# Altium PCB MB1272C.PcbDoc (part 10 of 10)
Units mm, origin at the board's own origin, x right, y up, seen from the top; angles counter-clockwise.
Board outline 101 x 71 mm, 6 copper layers (Top Layer, Signal Layer 1, Signal Layer 2, Signal Layer 3, Signal Layer 4, Bottom Layer), stack 1.552 mm thick; 520 components, 478 nets, 2156 pads, 1894 vias.

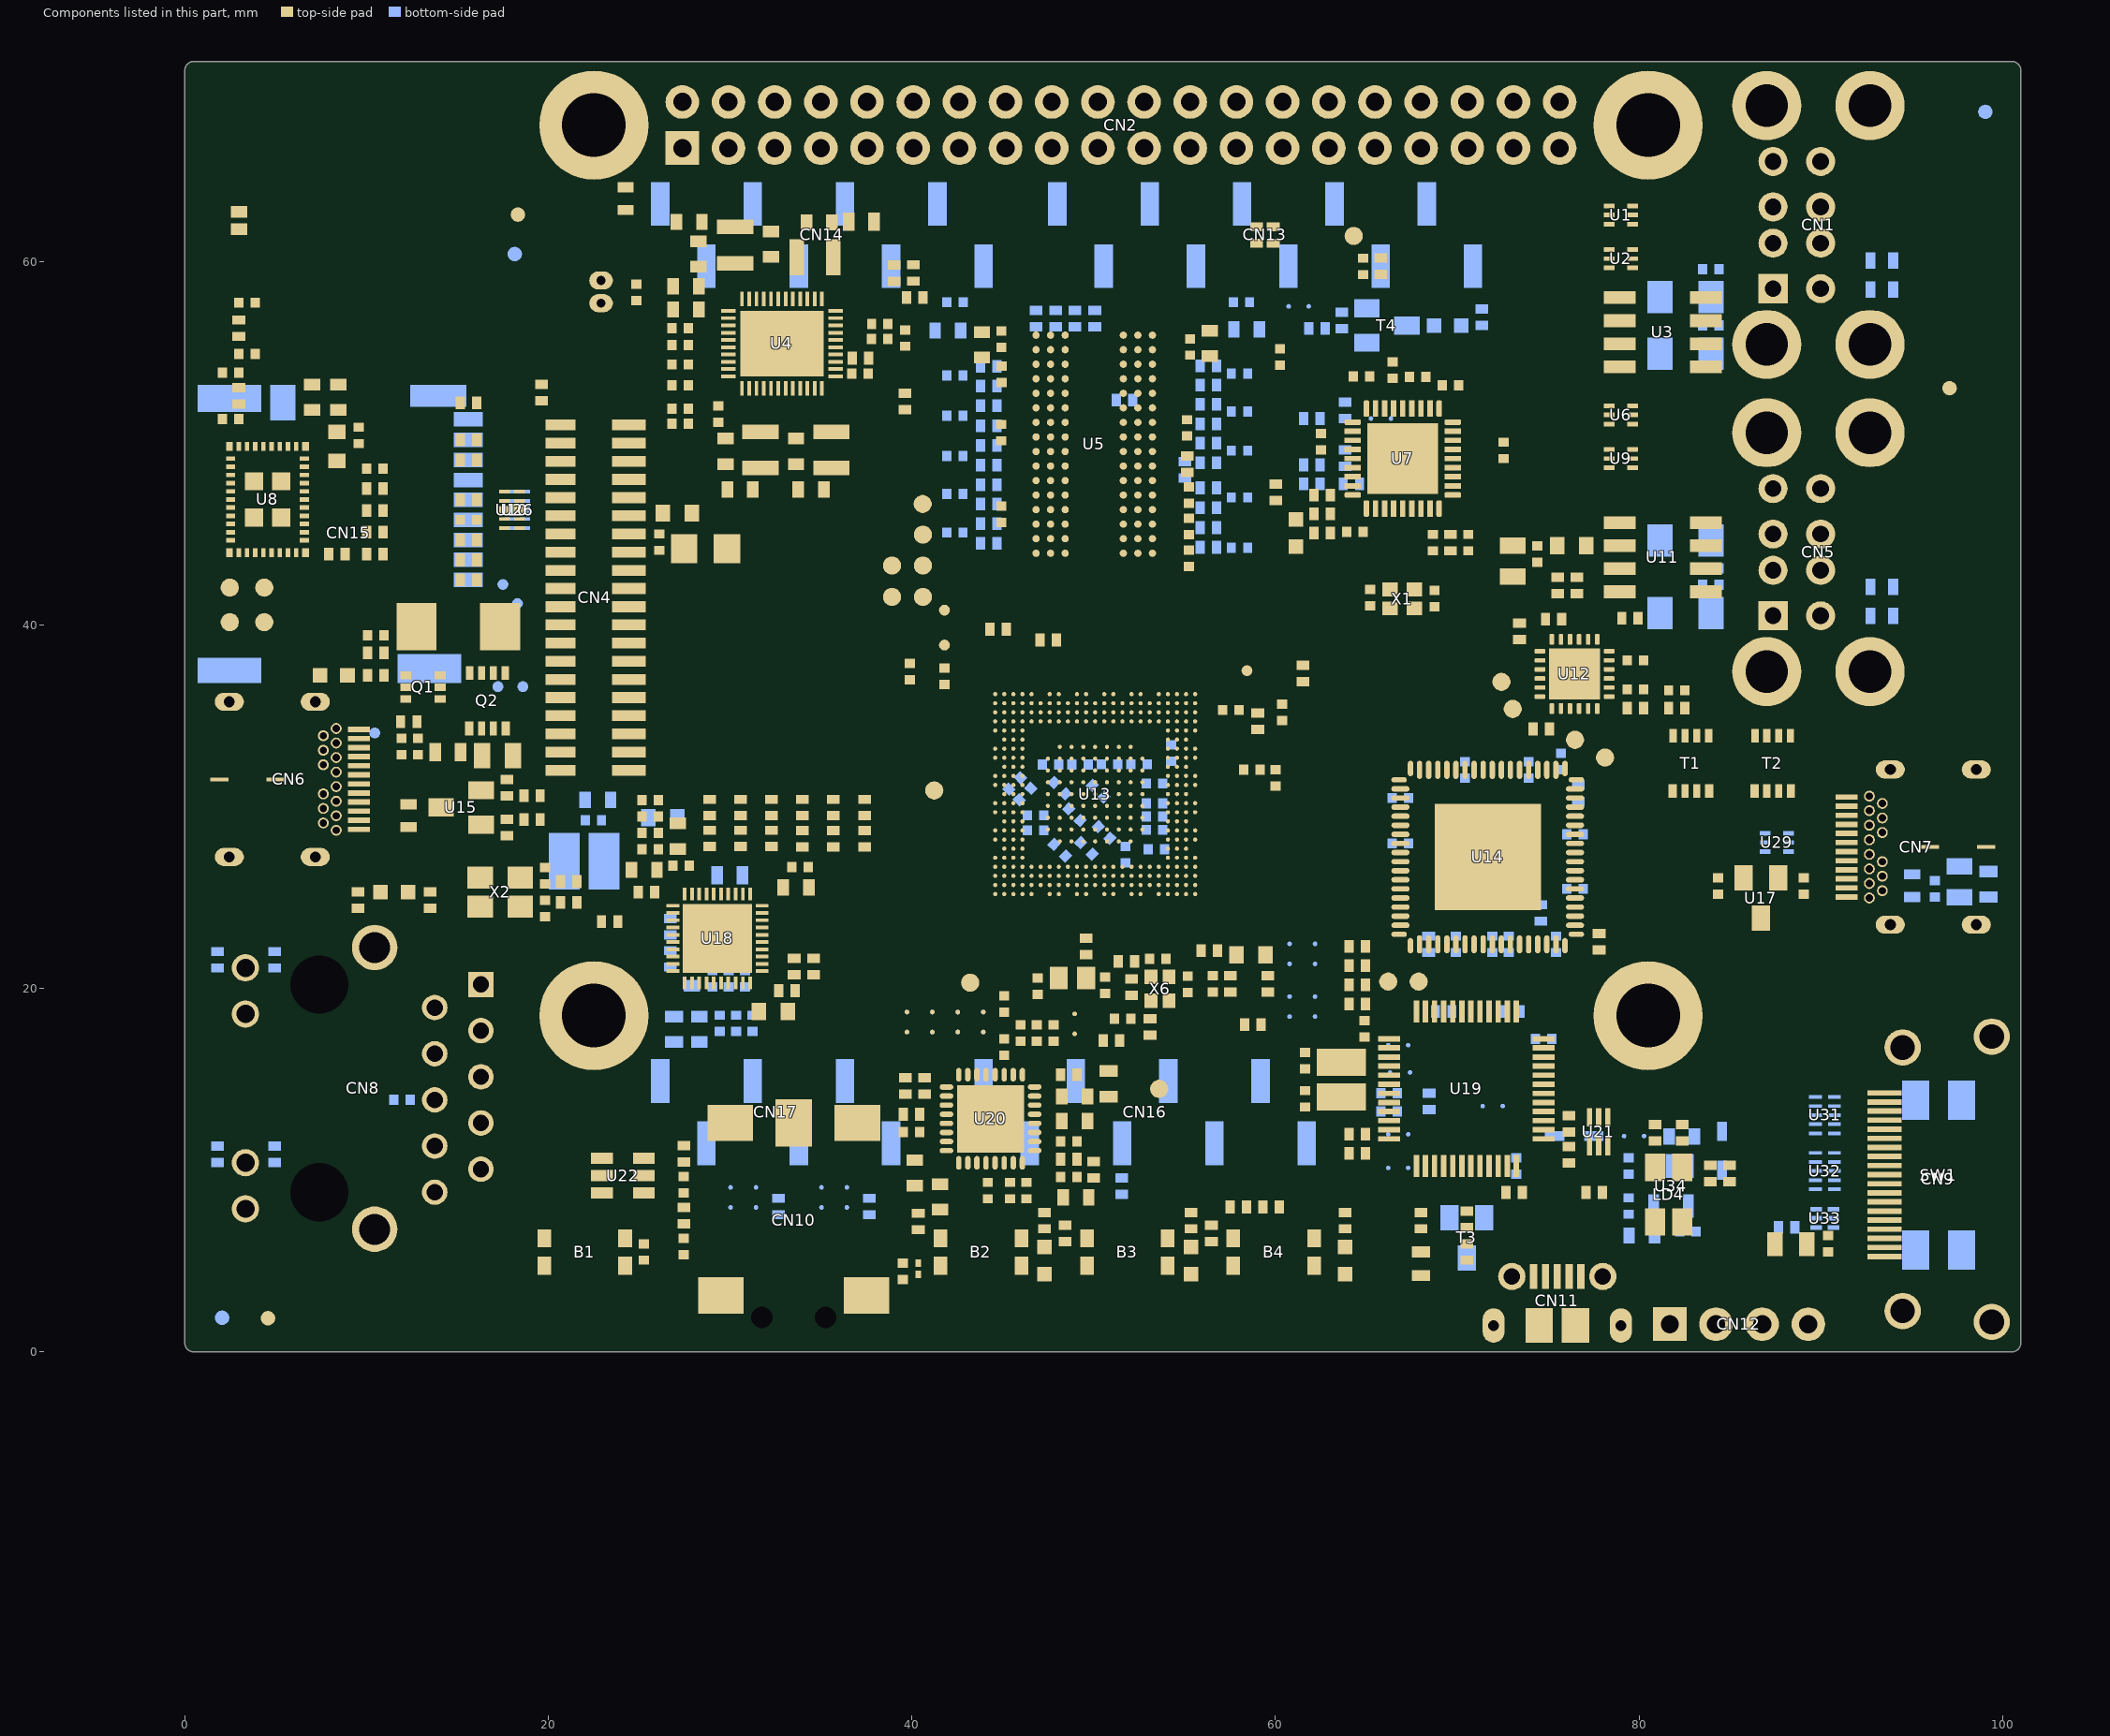
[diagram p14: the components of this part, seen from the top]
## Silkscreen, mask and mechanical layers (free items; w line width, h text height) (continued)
Drill Drawing:
  drawing of 549 lines, arcs and shapes, not listed
  text "PCB SPECIFICATIONS :" at 6.92,173.965 h3
  text "PCB : TYPE 4" at 155.276,173.613 h3
  text "MINIMUN PARAMETERS" at 192.17,173.59 h3
  text "A.   MATERIAL :" at 6.92,169.965 h3
  text "FR-4" at 45.42,169.965 h3
  text "TG-170" at 61.92,169.965 h3
  text "X  TG-150" at 80.17,169.965 h3
  text "TG-140" at 96.17,169.965 h3
  text "ASPECT-RATIO, AXE Z :" at 155.276,168.113 h3
  text "DEFAULT" at 192.17,168.09 h3
  text "B.   MATERIAL FAMILY :" at 6.92,166.965 h3
  text "N/A" at 45.42,166.965 h3
  text "C.   SOLDERMASK COLOR :" at 6.92,163.965 h3
  text "X  BLUE" at 45.42,163.965 h3
  text "WHITE" at 61.92,163.965 h3
  text "RED" at 80.17,163.965 h3
  text "BLACK" at 96.17,163.965 h3
  text "TRACKS : 0.090mm           / GAPS : 0.090mm" at 192.17,162.34 h3
  text "6:1 to 8:1 / LEVEL \"B\"" at 155.295,161.365 h3
  text "D.   SILKSCREEN COLOR :" at 6.92,160.965 h3
  text "X  WHITE" at 45.42,160.965 h3
  text "YELLOW" at 61.92,160.965 h3
  text "BLACK" at 80.17,160.965 h3
  text "Blue ink PANTONE 2955" at 96.17,160.965 h3
  text "MCU" at 192.495,158.265 h3
  text "E.   SURFACE FINISH :" at 6.92,157.965 h3
  text "X  ENIG" at 45.42,157.965 h3
  text "IMMERSION SILVER" at 61.92,157.965 h3
  text "IMMERSION TIN" at 96.17,157.965 h3
  text "HASL" at 45.42,154.965 h3
  text "HASL (PB-FREE)" at 61.92,154.965 h3
  text "GOLDEN FINGER" at 96.17,154.965 h3
  text "TRACKS : 0.090mm           / GAPS : 0.080mm" at 192.495,152.515 h3
  text "F.   IMPEDANCE CONTROL :" at 6.92,151.965 h3
  text "NO" at 45.42,151.965 h3
  text "X  YES  (SEE IMPEDANCE TABLE FOR DETAIL INFORMATION)" at 61.92,151.965 h3
  text "G.   THROUGH VIA :" at 6.92,148.965 h3
  text "PLUG THE VIAS WHICH ARE COVERED WITH SOLDERMASK ONE OR TWO SIDE." at 45.42,148.965 h3
  text "PLUG MATERIAL :" at 45.42,145.965 h3
  text "X  SOLDERMASK" at 70.92,145.965 h3
  text "NON-CONDUCTIVE EPOXY." at 96.17,145.965 h3
  text "H.   STACK-UP :" at 6.92,142.965 h3
  text "SEE LAYER STACK-UP SEQUENCE FOR OVERALL THICKNESS." at 45.42,142.965 h3
  text "Layer" at 157.322,132.1 h2
  text "Name" at 165.689,132.1 h2
  text "Material" at 181.863,132.1 h2
  text "Thickness" at 198.125,132.1 h2
  text "Constant" at 210.065,132.1 h2
  text "Board Layer Stack" at 221.117,132.1 h2
  text "IMPEDANCE TABLE     SDMMC1" at 63.325,131.975 h3
  text "IMPEDANCE TABLE     DDR" at -28.85,131.95 h3
  text "Top Overlay" at 165.689,128.1 h2
  text "LAYER" at -23.9,127 h3
  text "LAYER" at 67.575,126.975 h3
  text "TRACE" at 83.825,126.975 h3
  text "SPACING" at 94.325,126.975 h3
  text "IMPEDANCE" at 107.825,126.975 h3
  text "IMPEDANCE" at 124.825,126.975 h3
  text "TOL." at 143.575,126.975 h3
  text "TRACE" at -8.35,126.95 h3
  text "SPACING" at 2.15,126.95 h3
  text "IMPEDANCE" at 15.65,126.95 h3
  text "IMPEDANCE" at 32.65,126.95 h3
  text "TOL." at 51.4,126.95 h3
  text "(mm)" at 97.65,124.5 h2.5
  text "(mm)" at 5.475,124.475 h2.5
  text "(mm)" at 85.825,124.45 h2.5
  text "(mm)" at -6.35,124.425 h2.5
  text "(Single ended)" at 108.325,124.225 h2.5
  text "(Differential)" at 126.075,124.225 h2.5
  text "(Single ended)" at 16.15,124.2 h2.5
  text "(Differential)" at 33.9,124.2 h2.5
  text "Top Solder" at 165.689,124.1 h2
  text "Solder Resist" at 181.863,124.1 h2
  text "0,020mm" at 198.125,124.1 h2
  text "3.5" at 210.065,124.1 h2
  text "+/- 15%" at 142.63,120.585 h3
  text "0.130" at 84.8,120.5 h3
  text "0.120" at -7.375,120.475 h3
  text "0.260" at 96.825,120.475 h3
  text "0.300" at 4.65,120.45 h3
  text "+/- 10%" at 49.825,120.45 h3
  text "TOP/BOTTOM" at 63.805,120.46 h3
  text "50 ohm" at 111.18,120.41 h3
  text "55 ohm" at 19.005,120.385 h3
  text "NA" at 130.73,120.36 h3
  text "NA" at 38.555,120.335 h3
  text "1" at 157.322,120.1 h2
  text "Top Layer" at 165.689,120.1 h2
  text "0,035mm" at 198.125,120.1 h2
  text "TOP" at -22.075,118.825 h3
  text "+/- 15%" at 142.635,117.07 h3
  text "+/- 10%" at 49.85,117.05 h3
  text "NA" at 21.075,117 h3
  text "0.130" at 84.805,116.985 h3
  text "0.260" at 96.83,116.96 h3
  text "LAYER 2" at 67.25,116.925 h3
  text "100 ohm" at 35.05,116.9 h3
  text "50 ohm" at 111.185,116.895 h3
  text "NA" at 130.735,116.845 h3
  text "0.100/0.130/0.100" at -7.825,116.775 h3
  text "Dielectric 1" at 165.689,116.1 h2
  text "IT-180A 3313H" at 181.863,116.1 h2
  text "0,099mm" at 198.125,116.1 h2
  text "4.2" at 210.065,116.1 h2
  text "0.127" at -7.38,113.465 h3
  text "0.300" at 4.645,113.44 h3
  text "+/- 10%" at 49.82,113.44 h3
  text "55 ohm" at 19,113.375 h3
  text "NA" at 38.55,113.325 h3
  text "2" at 157.32,112.1 h2
  text "Signal Layer 1" at 165.689,112.1 h2
  text "0,035mm" at 198.125,112.1 h2
  text "LAYER 2" at -25.2,111.825 h3
  text "+/- 10%" at 49.845,110.04 h3
  text "NA" at 21.07,109.99 h3
  text "100 ohm" at 35.045,109.89 h3
  text "IMPEDANCE TABLE     USB" at 63.175,109.875 h3
  text "0.090/0.140/0.090" at -7.83,109.765 h3
  text "Dielectric 2" at 165.689,108.1 h2
  text "IT-180A" at 181.863,108.1 h2
  text "0,130mm" at 198.125,108.1 h2
  text "4.2" at 210.065,108.1 h2
  text "0.120" at -7.38,106.44 h3
  text "0.300" at 4.645,106.415 h3
  text "+/- 10%" at 49.82,106.415 h3
  text "55 ohm" at 19,106.35 h3
  text "NA" at 38.55,106.3 h3
  text "LAYER" at 67.425,104.875 h3
  text "TRACE" at 83.675,104.875 h3
  text "SPACING" at 94.175,104.875 h3
  text "IMPEDANCE" at 107.675,104.875 h3
  text "IMPEDANCE" at 124.675,104.875 h3
  text "TOL." at 143.425,104.875 h3
  text "BOTTOM" at -24.775,104.75 h3
  text "3" at 157.322,104.1 h2
  text "Signal Layer 2" at 165.689,104.1 h2
  text "0,035mm" at 198.125,104.1 h2
  text "+/- 10%" at 49.845,103.015 h3
  text "NA" at 21.07,102.965 h3
  text "100 ohm" at 35.045,102.865 h3
  text "0.100/0.130/0.100" at -7.83,102.74 h3
  text "(mm)" at 97.5,102.4 h2.5
  text "(mm)" at 85.675,102.35 h2.5
  text "(Single ended)" at 108.175,102.125 h2.5
  text "(Differential)" at 125.925,102.125 h2.5
  text "Dielectric 3" at 165.689,100.1 h2
  text "IT-180A 1080*2" at 181.863,100.1 h2
  text "0,885mm" at 198.125,100.1 h2
  text "4.25" at 210.065,100.1 h2
  text "0.100" at 84.65,98.4 h3
  text "NA" at 113.275,98.4 h3
  text "0.090" at 96.675,98.375 h3
  text "90 ohm" at 127.925,98.375 h3
  text "+/- 15%" at 141.925,98.375 h3
  text "TOP/BOTTOM" at 63.655,98.36 h3
  text "4" at 157.322,96.1 h2
  text "Signal Layer 3" at 165.689,96.1 h2
  text "0,035mm" at 198.125,96.1 h2
  text "IMPEDANCE TABLE     DSI" at 63.175,92.475 h3
  text "Dielectric 4" at 165.689,92.1 h2
  text "IT-180A" at 181.863,92.1 h2
  text "0,130mm" at 198.125,92.1 h2
  text "4.2" at 210.065,92.1 h2
  text "5" at 157.322,88.1 h2
  text "Signal Layer 4" at 165.689,88.1 h2
  text "0,035mm" at 198.125,88.1 h2
  text "LAYER" at 67.425,87.475 h3
  text "TRACE" at 83.675,87.475 h3
  text "SPACING" at 94.175,87.475 h3
  text "IMPEDANCE" at 107.675,87.475 h3
  text "IMPEDANCE" at 124.675,87.475 h3
  text "TOL." at 143.425,87.475 h3
  text "(mm)" at 97.5,85 h2.5
  text "(mm)" at 85.675,84.95 h2.5
  text "(Single ended)" at 108.175,84.725 h2.5
  text "(Differential)" at 125.925,84.725 h2.5
  text "Dielectric 5" at 165.689,84.1 h2
  text "IT-180A 3313H" at 181.863,84.1 h2
  text "0,099mm" at 198.125,84.1 h2
  text "4.2" at 210.065,84.1 h2
  text "0.100" at 84.65,81 h3
  text "NA" at 113.275,81 h3
  text "0.130" at 96.675,80.975 h3
  text "100 ohm" at 127.925,80.975 h3
  text "+/- 15%" at 141.925,80.975 h3
  text "TOP/BOTTOM" at 63.655,80.96 h3
  text "6" at 157.322,80.1 h2
  text "Bottom Layer" at 165.689,80.1 h2
  text "0,035mm" at 198.125,80.1 h2
  text "Bottom Solder" at 165.689,76.1 h2
  text "Solder Resist" at 181.863,76.1 h2
  text "0,020mm" at 198.125,76.1 h2
  text "3.5" at 210.065,76.1 h2
  text "Bottom Overlay" at 165.689,72.1 h2
  text "Symbol" at 114.769,63.495 h2.4
  text "Count" at 124.166,63.495 h2.4
  text "Hole Size" at 134.918,63.495 h2.4
  text "Plated" at 154.152,63.495 h2.4
  text "Hole Type" at 162.404,63.495 h2.4
  text "Drill Layer Pair" at 174.414,63.495 h2.4
  text "Hole Length" at 197.594,63.495 h2.4
  text "Routed Path Length" at 215.714,63.495 h2.4
  text "530" at 124.166,59.355 h2
  text "0,100mm (3,94mil)" at 134.918,59.355 h2
  text "PTH" at 154.152,59.355 h2
  text "Round" at 162.404,59.355 h2
  text "Top Layer - Signal Layer 1" at 174.414,59.355 h2
  text "-" at 197.594,59.355 h2
  text "-" at 215.714,59.355 h2
  text "O" at 113.981,59.101 h1.84
  text "912" at 124.166,55.215 h2
  text "0,200mm (7,87mil)" at 134.918,55.215 h2
  text "PTH" at 154.152,55.215 h2
  text "Round" at 162.404,55.215 h2
  text "Top Layer - Bottom Layer" at 174.414,55.215 h2
  text "-" at 197.594,55.215 h2
  text "-" at 215.714,55.215 h2
  text "452" at 124.166,51.076 h2
  text "0,300mm (11,81mil)" at 134.918,51.076 h2
  text "PTH" at 154.152,51.076 h2
  text "Round" at 162.404,51.076 h2
  text "Top Layer - Bottom Layer" at 174.414,51.076 h2
  text "-" at 197.594,51.076 h2
  text "-" at 215.714,51.076 h2
  text "28" at 124.166,46.936 h2
  text "0,400mm (15,75mil)" at 134.918,46.936 h2
  text "PTH" at 154.152,46.936 h2
  text "Round" at 162.404,46.936 h2
  text "Top Layer - Bottom Layer" at 174.414,46.936 h2
  text "-" at 197.594,46.936 h2
  text "-" at 215.714,46.936 h2
  text "I" at 114.288,46.682 h1.84
  text "2" at 124.166,42.796 h2
  text "0,500mm (19,69mil)" at 134.918,42.796 h2
  text "PTH" at 154.152,42.796 h2
  text "Round" at 162.404,42.796 h2
  text "Top Layer - Bottom Layer" at 174.414,42.796 h2
  text "-" at 197.594,42.796 h2
  text "-" at 215.714,42.796 h2
  text "J" at 113.981,42.542 h1.84
  text "8" at 124.166,38.656 h2
  text "0,600mm (23,62mil)" at 134.918,38.656 h2
  text "PTH" at 154.152,38.656 h2
  text "Slot" at 162.404,38.656 h2
  text "Top Layer - Bottom Layer" at 174.414,38.656 h2
  text "1,200mm (47,24mil)" at 197.594,38.656 h2
  text "0,600mm (23,62mil)" at 215.714,38.656 h2
  text "H" at 113.981,38.403 h1.84
  text "2" at 124.166,34.517 h2
  text "0,600mm (23,62mil)" at 134.918,34.517 h2
  text "PTH" at 154.152,34.517 h2
  text "Slot" at 162.404,34.517 h2
  text "Top Layer - Bottom Layer" at 174.414,34.517 h2
  text "1,300mm (51,18mil)" at 197.594,34.517 h2
  text "0,700mm (27,56mil)" at 215.714,34.517 h2
  text "A" at 113.981,34.263 h1.84
  text "12" at 124.166,30.377 h2
  text "0,900mm (35,43mil)" at 134.918,30.377 h2
  text "PTH" at 154.152,30.377 h2
  text "Round" at 162.404,30.377 h2
  text "Top Layer - Bottom Layer" at 174.414,30.377 h2
  text "-" at 197.594,30.377 h2
  text "-" at 215.714,30.377 h2
  text "16" at 124.166,26.237 h2
  text "0,920mm (36,22mil)" at 134.918,26.237 h2
  text "PTH" at 154.152,26.237 h2
  text "Round" at 162.404,26.237 h2
  text "Top Layer - Bottom Layer" at 174.414,26.237 h2
  text "-" at 197.594,26.237 h2
  text "-" at 215.714,26.237 h2
  text "F" at 113.981,25.984 h1.84
  text "48" at 124.166,22.098 h2
  text "1,000mm (39,37mil)" at 134.918,22.098 h2
  text "PTH" at 154.152,22.098 h2
  text "Round" at 162.404,22.098 h2
  text "Top Layer - Bottom Layer" at 174.414,22.098 h2
  text "-" at 197.594,22.098 h2
  text "-" at 215.714,22.098 h2
  text "2" at 124.166,17.958 h2
  text "1,200mm (47,24mil)" at 134.918,17.958 h2
  text "NPTH" at 154.152,17.958 h2
  text "Round" at 162.404,17.958 h2
  text "Top Layer - Bottom Layer" at 174.414,17.958 h2
  text "-" at 197.594,17.958 h2
  text "-" at 215.714,17.958 h2
  text "4" at 124.166,13.818 h2
  text "1,350mm (53,15mil)" at 134.918,13.818 h2
  text "PTH" at 154.152,13.818 h2
  text "Round" at 162.404,13.818 h2
  text "Top Layer - Bottom Layer" at 174.414,13.818 h2
  text "-" at 197.594,13.818 h2
  text "-" at 215.714,13.818 h2
  text "K" at 113.981,13.564 h1.84
  text "2" at 124.166,9.678 h2
  text "1,700mm (66,93mil)" at 134.918,9.678 h2
  text "PTH" at 154.152,9.678 h2
  text "Round" at 162.404,9.678 h2
  text "Top Layer - Bottom Layer" at 174.414,9.678 h2
  text "-" at 197.594,9.678 h2
  text "-" at 215.714,9.678 h2
  text "L" at 113.981,9.425 h1.84
  text "8" at 124.166,5.539 h2
  text "2,330mm (91,73mil)" at 134.918,5.539 h2
  text "PTH" at 154.152,5.539 h2
  text "Round" at 162.404,5.539 h2
  text "Top Layer - Bottom Layer" at 174.414,5.539 h2
  text "-" at 197.594,5.539 h2
  text "-" at 215.714,5.539 h2
  text "G" at 113.981,5.285 h1.84
  text "2" at 124.166,1.399 h2
  text "3,200mm (125,98mil)" at 134.918,1.399 h2
  text "NPTH" at 154.152,1.399 h2
  text "Round" at 162.404,1.399 h2
  text "Top Layer - Bottom Layer" at 174.414,1.399 h2
  text "-" at 197.594,1.399 h2
  text "-" at 215.714,1.399 h2
  text "M" at 113.981,1.145 h1.84
  text "4" at 124.166,-2.741 h2
  text "3,500mm (137,79mil)" at 134.918,-2.741 h2
  text "PTH" at 154.152,-2.741 h2
  text "Round" at 162.404,-2.741 h2
  text "Top Layer - Bottom Layer" at 174.414,-2.741 h2
  text "-" at 197.594,-2.741 h2
  text "-" at 215.714,-2.741 h2
  text "N" at 113.981,-2.994 h1.84
  text "2032 Total" at 124.166,-6.88 h2
  text "Slot definitions :" at 114.769,-9.778 h2
  text "Routed Path Length" at 128.391,-9.778 h2
  text "= Calculated from tool start centre position to tool end centre position." at 145.274,-9.778 h2
  text ".Layer_Name" at 14.068,-11.217 h3
  text ".DRL" at 55.763,-11.217 h3
  text "Hole Length" at 128.391,-11.434 h2
  text "= Routed Path Length + Tool Size = Slot length as defined in the PCB layout" at 139.007,-11.434 h2
M20-Top Sheet Box:
  circle w0.254: c92.072,-17.938 r1.3
  region: 77.594,-19.031 66.838,-19.031 67.832,-16.538 75.689,-16.538 76.138,-15.779 78.347,-18.327
  region: 91.598,-10.701 76.07,-10.701 75.376,-12.477 74.165,-13.702 72.768,-11.842 72.768,-10.191 73.911,-8.794 75.347,-8.415 91.598,-8.415
  lines w0.254: 67.832,-16.538 76.624,-16.538 73.557,-13 cw(c75.361,-11.056) 75.601,-8.415 92.365,-8.415 91.603,-10.701 ; 71.145,-8.168 cw(c73.572,-9.139) 73.808,-6.536 ; 71.185,-8.136 66.838,-19.031 86.161,-19.031 ccw(c86.41,-16.296) 88.959,-17.316 ; 72.924,-12.07 78.347,-18.327 ; 73.178,-12.07 78.483,-18.192 ; 73.178,-11.816 78.483,-17.938 ; 73.276,-10.701 86.269,-10.701 ; 73.305,-11.689 78.61,-17.811 ; 73.432,-11.562 78.737,-17.684 ; 73.559,-11.435 78.864,-17.557 ; 73.686,-11.308 78.991,-17.43 ; 73.741,-9.356 79.046,-15.477 ; 73.809,-6.536 93.259,-6.536 88.96,-17.314 ; 73.813,-11.181 79.064,-17.24 ; 73.813,-10.927 79.118,-17.049 ; 73.813,-10.673 79.118,-16.795 ; 73.813,-9.784 79.118,-15.906 ; 73.94,-10.546 79.245,-16.668 ; 73.94,-10.165 79.245,-16.287 ; 75.312,-16.551 ccw(c75.417,-16.016) 75.715,-15.559 ; 76.399,-10.688 ccw(c76.373,-11.255) 76.042,-11.717 78.407,-14.446 cw(c76.603,-16.39) 77.336,-18.939 ; 82.68,-18.827 85.569,-10.447 ; 82.902,-18.777 85.771,-10.456 ; 83.029,-18.777 85.898,-10.456 ; 83.283,-18.777 86.152,-10.456 ; 83.537,-18.777 86.406,-10.456 ; 83.791,-18.777 86.66,-10.456 ; 84.045,-18.777 86.914,-10.456 ; 84.299,-18.777 87.168,-10.456 ; 84.553,-18.777 87.422,-10.456 ; 84.807,-18.777 87.676,-10.456 ; 85.016,-18.827 87.905,-10.447 ; 87.905,-10.701 91.598,-10.701 ; 90.929,-10.699 91.691,-8.413 ; 91.095,-10.701 91.857,-8.415 ; 91.349,-10.701 92.111,-8.415
  lines w0.3: 5.068,-22.917 95.068,-22.917 95.068,-2.917 5.068,-2.917 ; 5.068,-17.917 65.068,-17.917 ; 5.068,-12.917 65.068,-12.917 ; 5.068,-7.917 65.068,-7.917 ; 5.068,-22.917 5.068,-2.917 ; 45.068,-22.917 45.068,-7.917 ; 65.068,-22.917 65.068,-2.917 ; 82.68,-18.827 85.016,-18.827
  text "Project: '.Board_Name'" at 6.068,-6.133 h3
  text "Layer:" at 6.068,-11.217 h3
  text "Gerber:" at 46.057,-11.217 h3
  text "Variant: '.VariantName'" at 6.068,-16.217 h3
  text "Ref: MB1272" at 46.184,-16.217 h3
  text "R" at 91.564,-18.7 h1.52
  text "Date: 18-SEPT-26" at 6.068,-21.217 h3
  text "Rev: '.Board_PCB_Revision'" at 46.127,-21.217 h3
M21-Bottom Sheet Box:
  circle w0.254: c8.251,-17.938 r1.3
  region: 8.726,-10.701 24.253,-10.701 24.947,-12.477 26.158,-13.702 27.555,-11.842 27.555,-10.191 26.412,-8.794 24.976,-8.415 8.726,-8.415
  region: 22.729,-19.031 33.485,-19.031 32.492,-16.538 24.634,-16.538 24.185,-15.779 21.977,-18.327
  lines w0.254: 8.212,-8.415 8.974,-10.701 ; 8.466,-8.415 9.228,-10.701 ; 8.632,-8.413 9.394,-10.699 ; 8.72,-10.701 7.958,-8.415 24.722,-8.415 cw(c24.962,-11.056) 26.766,-13 23.7,-16.538 32.492,-16.538 ; 8.726,-10.701 12.418,-10.701 ; 11.363,-17.314 7.064,-6.536 26.514,-6.536 ; 11.364,-17.316 ccw(c13.914,-16.296) 14.162,-19.031 33.485,-19.031 29.139,-8.136 ; 12.418,-10.447 15.307,-18.827 ; 12.647,-10.456 15.516,-18.777 ; 12.901,-10.456 15.77,-18.777 ; 13.155,-10.456 16.024,-18.777 ; 13.409,-10.456 16.278,-18.777 ; 13.663,-10.456 16.532,-18.777 ; 13.917,-10.456 16.786,-18.777 ; 14.054,-10.701 27.047,-10.701 ; 14.171,-10.456 17.04,-18.777 ; 14.425,-10.456 17.294,-18.777 ; 14.552,-10.456 17.421,-18.777 ; 14.754,-10.447 17.643,-18.827 ; 21.078,-16.668 26.383,-10.546 ; 21.078,-16.287 26.383,-10.165 ; 21.205,-17.049 26.51,-10.927 ; 21.205,-16.795 26.51,-10.673 ; 21.205,-15.906 26.51,-9.784 ; 21.259,-17.24 26.51,-11.181 ; 21.277,-15.477 26.582,-9.356 ; 21.332,-17.43 26.637,-11.308 ; 21.459,-17.557 26.764,-11.435 ; 21.586,-17.684 26.891,-11.562 ; 21.713,-17.811 27.018,-11.689 ; 21.84,-18.192 27.145,-12.07 ; 21.84,-17.938 27.145,-11.816 ; 21.977,-18.327 27.399,-12.07 ; 22.987,-18.939 cw(c23.72,-16.39) 21.916,-14.446 24.281,-11.717 ccw(c23.951,-11.255) 23.925,-10.688 ; 24.608,-15.559 ccw(c24.906,-16.016) 25.011,-16.551 ; 26.515,-6.536 cw(c26.752,-9.139) 29.178,-8.168
  lines w0.3: 15.307,-18.827 17.643,-18.827 ; 35.068,-22.917 35.068,-2.917 ; 35.068,-17.917 95.068,-17.917 ; 35.068,-12.917 95.068,-12.917 ; 35.068,-7.917 95.068,-7.917 ; 55.068,-22.917 55.068,-7.917 ; 5.068,-22.917 5.068,-2.917 95.068,-2.917 95.068,-22.917 5.068,-22.917
  text "Project: '.Board_Name'" at 93.874,-6.133 h3
  text "Gerber:" at 53.885,-11.217 h3
  text "Layer:" at 93.874,-11.217 h3
  text "Ref: MB1272" at 53.885,-16.217 h3
  text "Variant: '.VariantName'" at 93.874,-16.217 h3
  text "R" at 8.759,-18.7 h1.52
  text "Rev: '.Board_PCB_Revision'" at 53.942,-21.217 h3
  text "Date: 18-SEPT-26" at 93.874,-21.217 h3

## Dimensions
0,70.5 to 101,70.5 on M2-Board Dimensions
0.5,71 to 0.5,0 on M2-Board Dimensions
